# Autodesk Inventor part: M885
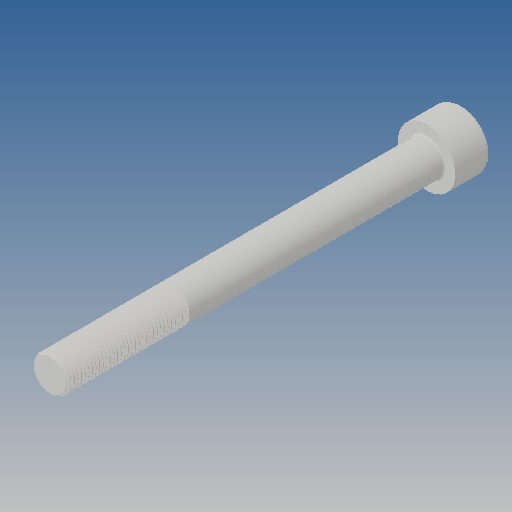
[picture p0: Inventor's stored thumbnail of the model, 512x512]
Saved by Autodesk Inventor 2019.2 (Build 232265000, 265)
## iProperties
Created: 2013-07
Part Number: M885
Material: Ogólny
Document SubType Name: Modeling
Designer: CADENGINEERING4
Density: 1 g/cm^3
Appearance: Domyślna
Author: CADENGINEERING4
Revision Number: ÈÎºÎ
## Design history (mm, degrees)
feature "gb70M8x85_GB_FASTENER_SCREWS_HSHCS M8X80-N-2-solid1"
node "Bryła1"
